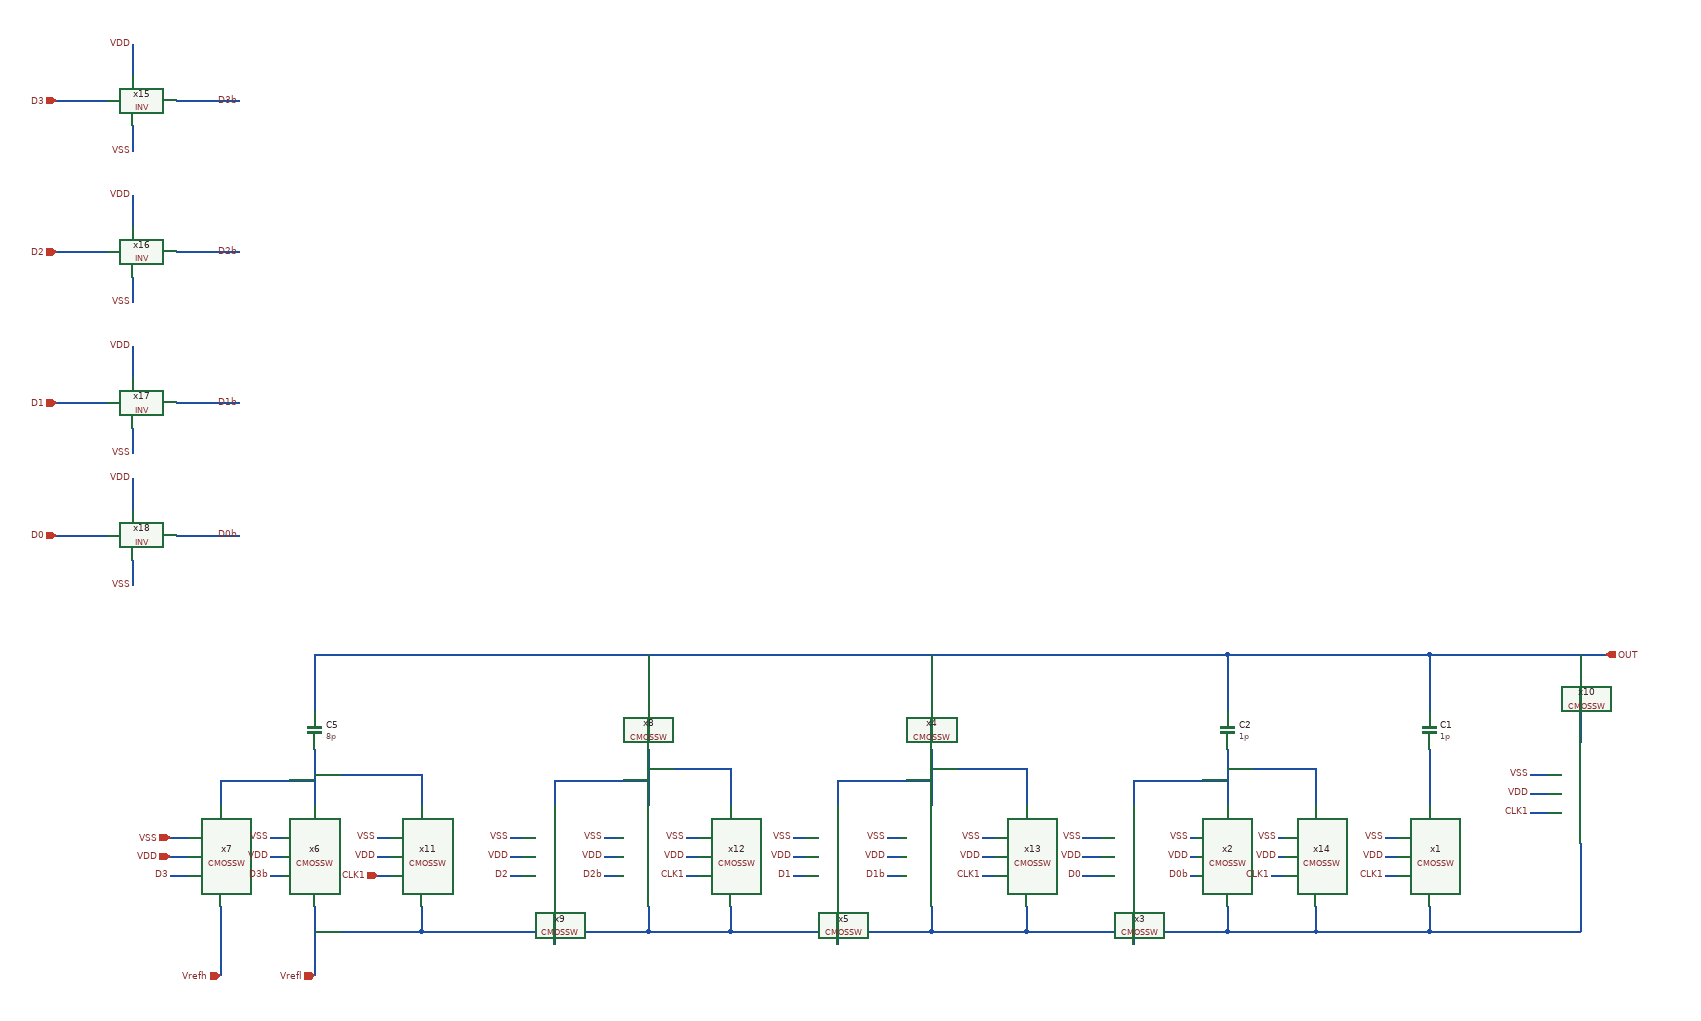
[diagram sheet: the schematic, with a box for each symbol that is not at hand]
v {xschem version=3.4.8RC file_version=1.2}
G {}
K {}
V {}
S {}
E {}
N 370 -150 370 -60 {lab=OUT}
N 50 -150 50 -60 {lab=OUT}
N -420 -150 -420 -60 {lab=OUT}
N -870 -150 -870 -60 {lab=OUT}
N -1400 -150 -1400 -60 {lab=OUT}
N -30 -150 50 -150 {lab=OUT}
N 50 -150 120 -150 {lab=OUT}
N 540 -150 650 -150 {lab=OUT}
N 370 -0 370 90 {lab=#net1}
N 200 -150 370 -150 {lab=OUT}
N 50 0 50 90 {lab=#net2}
N -100 50 -100 90 {lab=#net2}
N -100 50 50 50 {lab=#net2}
N -450 -150 -210 -150 {lab=OUT}
N -420 0 -420 90 {lab=#net3}
N -570 50 -570 90 {lab=#net3}
N -570 50 -420 50 {lab=#net3}
N -970 -150 -660 -150 {lab=OUT}
N -1400 0 -1400 90 {lab=#net4}
N -1550 50 -1550 90 {lab=#net4}
N -1550 50 -1400 50 {lab=#net4}
N -1340 -150 -1040 -150 {lab=OUT}
N -870 0 -870 90 {lab=#net5}
N -1020 50 -1020 90 {lab=#net5}
N -1020 50 -870 50 {lab=#net5}
N -1550 250 -1550 360 {lab=Vrefh}
N -1400 250 -1400 360 {lab=Vrefl}
N -100 250 -100 310 {lab=#net6}
N -570 250 -570 310 {lab=#net7}
N -1020 250 -1020 310 {lab=#net8}
N 370 250 370 290 {lab=Vrefl}
N 50 250 50 290 {lab=Vrefl}
N -420 250 -420 290 {lab=Vrefl}
N -870 250 -870 290 {lab=Vrefl}
N -1630 140 -1600 140 {lab=VSS}
N -1470 140 -1450 140 {lab=VSS}
N -1090 140 -1070 140 {lab=VSS}
N -940 140 -920 140 {lab=VSS}
N -640 140 -620 140 {lab=VSS}
N -10 140 0 140 {lab=VSS}
N 300 140 320 140 {lab=VSS}
N -1630 170 -1600 170 {lab=VDD}
N -1470 170 -1450 170 {lab=VDD}
N -1090 170 -1070 170 {lab=VDD}
N -940 170 -920 170 {lab=VDD}
N -640 170 -620 170 {lab=VDD}
N -10 170 0 170 {lab=VDD}
N 300 170 320 170 {lab=VDD}
N -1630 200 -1600 200 {lab=D3}
N -1470 200 -1450 200 {lab=D3b}
N 370 -150 540 -150 {lab=OUT}
N 610 -150 610 -10 {lab=OUT}
N 610 150 610 290 {lab=Vrefl}
N 370 290 610 290 {lab=Vrefl}
N 530 40 560 40 {lab=VSS}
N 530 70 560 70 {lab=VDD}
N 530 100 560 100 {lab=CLK1}
N 300 200 320 200 {lab=CLK1}
N -1090 200 -1070 200 {lab=D2}
N -940 200 -920 200 {lab=D2b}
N -640 200 -620 200 {lab=D1}
N -10 200 0 200 {lab=D0b}
N -1300 140 -1280 140 {lab=VSS}
N -1300 170 -1280 170 {lab=VDD}
N -1300 200 -1280 200 {lab=CLK1}
N -1230 40 -1230 90 {lab=#net4}
N -1400 40 -1230 40 {lab=#net4}
N -1400 290 -1230 290 {lab=Vrefl}
N -1400 -150 -1340 -150 {lab=OUT}
N -1040 -150 -970 -150 {lab=OUT}
N -810 140 -790 140 {lab=VSS}
N -810 170 -790 170 {lab=VDD}
N -810 200 -790 200 {lab=CLK1}
N -740 70 -740 90 {lab=#net5}
N -870 30 -740 30 {lab=#net5}
N -740 30 -740 70 {lab=#net5}
N -270 30 -270 90 {lab=#net3}
N -420 30 -270 30 {lab=#net3}
N 190 30 190 90 {lab=#net2}
N 50 30 190 30 {lab=#net2}
N -1230 250 -1230 290 {lab=Vrefl}
N -1230 290 -870 290 {lab=Vrefl}
N -870 290 -740 290 {lab=Vrefl}
N -740 250 -740 290 {lab=Vrefl}
N -740 290 -420 290 {lab=Vrefl}
N -420 290 -270 290 {lab=Vrefl}
N -270 250 -270 290 {lab=Vrefl}
N -270 290 50 290 {lab=Vrefl}
N 50 290 190 290 {lab=Vrefl}
N 190 250 190 290 {lab=Vrefl}
N 190 290 370 290 {lab=Vrefl}
N -660 -150 -450 -150 {lab=OUT}
N -210 -150 -30 -150 {lab=OUT}
N 120 -150 200 -150 {lab=OUT}
N 120 200 140 200 {lab=CLK1}
N -340 200 -320 200 {lab=CLK1}
N -1810 -1030 -1730 -1030 {lab=D3}
N -1620 -1030 -1520 -1030 {lab=D3b}
N -1690 -1120 -1690 -1070 {lab=VDD}
N -1690 -990 -1690 -950 {lab=VSS}
N -1810 -790 -1730 -790 {lab=D2}
N -1620 -790 -1520 -790 {lab=D2b}
N -1690 -880 -1690 -830 {lab=VDD}
N -1690 -750 -1690 -710 {lab=VSS}
N -1810 -550 -1730 -550 {lab=D1}
N -1620 -550 -1520 -550 {lab=D1b}
N -1690 -640 -1690 -590 {lab=VDD}
N -1690 -510 -1690 -470 {lab=VSS}
N -1810 -340 -1730 -340 {lab=D0}
N -1620 -340 -1520 -340 {lab=D0b}
N -1690 -430 -1690 -380 {lab=VDD}
N -1690 -300 -1690 -260 {lab=VSS}
N -490 140 -470 140 {lab=VSS}
N -490 170 -470 170 {lab=VDD}
N -340 140 -320 140 {lab=VSS}
N -340 170 -320 170 {lab=VDD}
N -180 140 -150 140 {lab=VSS}
N -180 170 -150 170 {lab=VDD}
N 130 140 140 140 {lab=VSS}
N 130 170 140 170 {lab=VDD}
N -490 200 -470 200 {lab=D1b}
N -180 200 -150 200 {lab=D0}
C {capa.sym} 370 -30 0 0 {name=C1
m=1
value=1p
footprint=1206
device="ceramic capacitor"}
C {capa.sym} 50 -30 0 0 {name=C2
m=1
value=1p
footprint=1206
device="ceramic capacitor"}
C {capa.sym} -420 -30 0 0 {name=C3
m=1
value=2p
footprint=1206
device="ceramic capacitor"}
C {capa.sym} -870 -30 0 0 {name=C4
m=1
value=4p
footprint=1206
device="ceramic capacitor"}
C {capa.sym} -1400 -30 0 0 {name=C5
m=1
value=8p
footprint=1206
device="ceramic capacitor"}
C {opin.sym} 650 -150 0 0 {name=p1 lab=OUT}
C {C:/Users/ISLab2/Documents/minimal_LR/CMOSSW.sym} 370 100 3 0 {name=x1}
C {C:/Users/ISLab2/Documents/minimal_LR/CMOSSW.sym} 50 100 3 0 {name=x2}
C {C:/Users/ISLab2/Documents/minimal_LR/CMOSSW.sym} -100 100 3 0 {name=x3}
C {C:/Users/ISLab2/Documents/minimal_LR/CMOSSW.sym} -420 100 3 0 {name=x4}
C {C:/Users/ISLab2/Documents/minimal_LR/CMOSSW.sym} -570 100 3 0 {name=x5}
C {C:/Users/ISLab2/Documents/minimal_LR/CMOSSW.sym} -1400 100 3 0 {name=x6}
C {C:/Users/ISLab2/Documents/minimal_LR/CMOSSW.sym} -1550 100 3 0 {name=x7}
C {C:/Users/ISLab2/Documents/minimal_LR/CMOSSW.sym} -870 100 3 0 {name=x8}
C {iopin.sym} -1550 360 1 0 {name=p2 lab=Vrefh}
C {iopin.sym} -1400 360 1 0 {name=p3 lab=Vrefl}
C {iopin.sym} -1630 140 2 0 {name=p4 lab=VSS}
C {lab_wire.sym} 300 140 0 0 {name=p5 sig_type=std_logic lab=VSS}
C {lab_wire.sym} -10 140 0 0 {name=p6 sig_type=std_logic lab=VSS}
C {lab_wire.sym} -940 140 0 0 {name=p10 sig_type=std_logic lab=VSS}
C {lab_wire.sym} -1090 140 0 0 {name=p11 sig_type=std_logic lab=VSS}
C {lab_wire.sym} -1470 140 0 0 {name=p12 sig_type=std_logic lab=VSS}
C {iopin.sym} -1630 170 2 0 {name=p13 lab=VDD}
C {lab_wire.sym} -1470 170 0 0 {name=p14 sig_type=std_logic lab=VDD}
C {lab_wire.sym} -1090 170 0 0 {name=p15 sig_type=std_logic lab=VDD}
C {lab_wire.sym} -940 170 0 0 {name=p16 sig_type=std_logic lab=VDD}
C {lab_wire.sym} -10 170 0 0 {name=p20 sig_type=std_logic lab=VDD}
C {lab_wire.sym} 300 170 0 0 {name=p21 sig_type=std_logic lab=VDD}
C {C:/Users/ISLab2/Documents/minimal_LR/CMOSSW.sym} 610 0 3 0 {name=x10}
C {lab_wire.sym} 530 40 0 0 {name=p22 sig_type=std_logic lab=VSS}
C {lab_wire.sym} 530 70 0 0 {name=p23 sig_type=std_logic lab=VDD}
C {C:/Users/ISLab2/Documents/minimal_LR/CMOSSW.sym} -1230 100 3 0 {name=x11}
C {lab_wire.sym} -1300 140 0 0 {name=p24 sig_type=std_logic lab=VSS}
C {lab_wire.sym} -1300 170 0 0 {name=p25 sig_type=std_logic lab=VDD}
C {C:/Users/ISLab2/Documents/minimal_LR/CMOSSW.sym} -1020 100 3 0 {name=x9}
C {C:/Users/ISLab2/Documents/minimal_LR/CMOSSW.sym} -740 100 3 0 {name=x12}
C {lab_wire.sym} -810 140 0 0 {name=p8 sig_type=std_logic lab=VSS}
C {lab_wire.sym} -810 170 0 0 {name=p9 sig_type=std_logic lab=VDD}
C {C:/Users/ISLab2/Documents/minimal_LR/CMOSSW.sym} -270 100 3 0 {name=x13}
C {C:/Users/ISLab2/Documents/minimal_LR/CMOSSW.sym} 190 100 3 0 {name=x14}
C {iopin.sym} -1300 200 2 0 {name=p17 lab=CLK1}
C {lab_wire.sym} -810 200 0 0 {name=p18 sig_type=std_logic lab=CLK1}
C {lab_wire.sym} -340 200 0 0 {name=p26 sig_type=std_logic lab=CLK1}
C {lab_wire.sym} 120 200 0 0 {name=p27 sig_type=std_logic lab=CLK1}
C {lab_wire.sym} 300 200 0 0 {name=p28 sig_type=std_logic lab=CLK1}
C {lab_wire.sym} 530 100 0 0 {name=p29 sig_type=std_logic lab=CLK1}
C {ipin.sym} -1810 -1030 0 0 {name=p30 lab=D3}
C {C:/Users/ISLab2/Documents/minimal_LR/INV.sym} -1580 -1030 0 0 {name=x15}
C {lab_wire.sym} -1520 -1030 0 0 {name=p31 sig_type=std_logic lab=D3b}
C {lab_wire.sym} -1690 -1120 0 0 {name=p32 sig_type=std_logic lab=VDD}
C {lab_wire.sym} -1690 -950 0 0 {name=p33 sig_type=std_logic lab=VSS}
C {ipin.sym} -1810 -790 0 0 {name=p34 lab=D2}
C {C:/Users/ISLab2/Documents/minimal_LR/INV.sym} -1580 -790 0 0 {name=x16}
C {lab_wire.sym} -1520 -790 0 0 {name=p35 sig_type=std_logic lab=D2b}
C {lab_wire.sym} -1690 -880 0 0 {name=p36 sig_type=std_logic lab=VDD}
C {lab_wire.sym} -1690 -710 0 0 {name=p37 sig_type=std_logic lab=VSS}
C {ipin.sym} -1810 -550 0 0 {name=p38 lab=D1}
C {C:/Users/ISLab2/Documents/minimal_LR/INV.sym} -1580 -550 0 0 {name=x17}
C {lab_wire.sym} -1520 -550 0 0 {name=p39 sig_type=std_logic lab=D1b}
C {lab_wire.sym} -1690 -640 0 0 {name=p40 sig_type=std_logic lab=VDD}
C {lab_wire.sym} -1690 -470 0 0 {name=p41 sig_type=std_logic lab=VSS}
C {ipin.sym} -1810 -340 0 0 {name=p42 lab=D0}
C {C:/Users/ISLab2/Documents/minimal_LR/INV.sym} -1580 -340 0 0 {name=x18}
C {lab_wire.sym} -1520 -340 0 0 {name=p43 sig_type=std_logic lab=D0b}
C {lab_wire.sym} -1690 -430 0 0 {name=p44 sig_type=std_logic lab=VDD}
C {lab_wire.sym} -1690 -260 0 0 {name=p45 sig_type=std_logic lab=VSS}
C {lab_wire.sym} -1630 200 0 0 {name=p46 sig_type=std_logic lab=D3}
C {lab_wire.sym} -1470 200 0 0 {name=p47 sig_type=std_logic lab=D3b}
C {lab_wire.sym} -1090 200 0 0 {name=p48 sig_type=std_logic lab=D2}
C {lab_wire.sym} -940 200 0 0 {name=p49 sig_type=std_logic lab=D2b}
C {lab_wire.sym} -640 140 0 0 {name=p50 sig_type=std_logic lab=VSS}
C {lab_wire.sym} -640 170 0 0 {name=p51 sig_type=std_logic lab=VDD}
C {lab_wire.sym} -490 140 0 0 {name=p52 sig_type=std_logic lab=VSS}
C {lab_wire.sym} -490 170 0 0 {name=p53 sig_type=std_logic lab=VDD}
C {lab_wire.sym} -340 140 0 0 {name=p54 sig_type=std_logic lab=VSS}
C {lab_wire.sym} -340 170 0 0 {name=p55 sig_type=std_logic lab=VDD}
C {lab_wire.sym} -180 140 0 0 {name=p56 sig_type=std_logic lab=VSS}
C {lab_wire.sym} -180 170 0 0 {name=p57 sig_type=std_logic lab=VDD}
C {lab_wire.sym} 130 140 0 0 {name=p7 sig_type=std_logic lab=VSS}
C {lab_wire.sym} 130 170 0 0 {name=p19 sig_type=std_logic lab=VDD}
C {lab_wire.sym} -640 200 0 0 {name=p58 sig_type=std_logic lab=D1}
C {lab_wire.sym} -490 200 0 0 {name=p59 sig_type=std_logic lab=D1b}
C {lab_wire.sym} -10 200 0 0 {name=p60 sig_type=std_logic lab=D0b}
C {lab_wire.sym} -180 200 0 0 {name=p61 sig_type=std_logic lab=D0}
